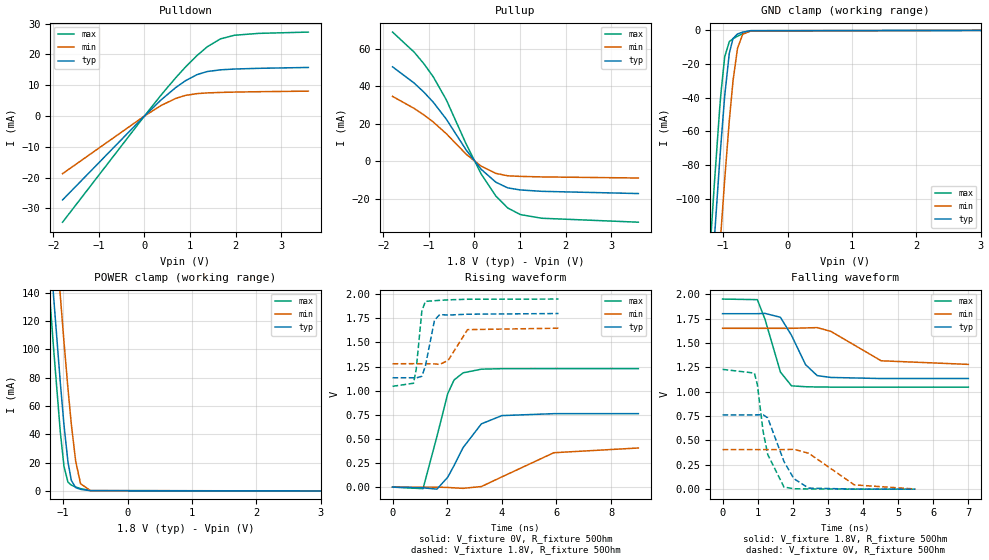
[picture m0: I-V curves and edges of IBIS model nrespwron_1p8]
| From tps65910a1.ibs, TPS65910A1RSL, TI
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|   nrespwron_1p8 Model
[Model]   nrespwron_1p8
Model_type   3-state
Polarity   Non-Inverting
Vmeas = 0.9
Vref = 0
Cref = 35pF
Rref = 150
|   typ   min   max
|   (nom PVT)   (fast PVT)   (slow PVT)
C_comp   6.512e-13   6.210e-13   7.537e-13
| Where nom  PVT is Nominal Process, 1.8V, 27C
|   Fast PVT is Strong Process,  1.95V, -40C
|   Slow PVT is Weak Process,   1.65V, 125C
[Voltage Range]   1.8   1.65   1.95
|Junction Temperature
[Temperature Range]   27   125   -40
[Pullup Reference]   1.8   1.65   1.95
[Pulldown Reference]   0   0   0
[Power Clamp Reference]   1.8   1.65   1.95
[GND Clamp Reference]   0   0   0
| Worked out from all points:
|   slope of the pulldown table from 0 to 0.27 V, typ, clamps not added: 68.9 ohm
|   slope of the pullup table from 0 to 0.27 V, typ, clamps not added: 37.4 ohm
|   GND clamp passes 1 mA (typ) near -0.69 V on its own axis
|   POWER clamp passes 1 mA (typ) near -0.71 V on its own axis
|   falling waveform, V_fixture 1.8V, R_fixture 50Ohm: 20-80 % time 557ps typ, 985ps min, 436ps max; typ from 1.8 V to 1.14 V
|   rising waveform, V_fixture 0V, R_fixture 50Ohm: 20-80 % time 952ps typ, 1.63ns min, 632ps max; typ from 0 V to 0.762 V
|   rising waveform, V_fixture 1.8V, R_fixture 50Ohm: 20-80 % time 265ps typ, 416ps min, 180ps max; typ from 1.13 V to 1.8 V
|   falling waveform, V_fixture 0V, R_fixture 50Ohm: 20-80 % time 472ps typ, 845ps min, 356ps max; typ from 0.762 V to 0 V
[Pulldown]
|   Voltage   I(typ)   I(min)   I(max)
-1.8V     -27.27mA   -18.74mA   -34.5mA
0V        0A         0A         0A
368.4mV   5.271mA    3.439mA    6.872mA
684mV     9.199mA    5.683mA    12.38mA
900mV     11.45mA    6.684mA    15.89mA
1.154V    13.43mA    7.265mA    19.64mA
1.38V     14.44mA    7.493mA    22.48mA
1.667V    14.99mA    7.652mA    25.03mA
1.979V    15.25mA    7.761mA    26.23mA
2.508V    15.48mA    7.885mA    26.83mA
3.6V      15.76mA    8.071mA    27.25mA
[GND Clamp]
|   Voltage   I(typ)   I(min)   I(max)
-1.8V     -537.9mA   -584.9mA   -510.2mA
-1.192V   -156.1mA   -209.6mA   -123.3mA
-1.139V   -125.2mA   -178.8mA   -92.45mA
-1.053V   -76.85mA   -129.7mA   -45.89mA
-1.031V   -65.74mA   -118.1mA   -35.95mA
-975.6mV  -38.78mA   -88.35mA   -15.65mA
-904.1mV  -13.48mA   -53.46mA   -6.697mA
-846.3mV  -4.832mA   -29.82mA   -4.985mA
-777mV    -2.173mA   -10.69mA   -3.501mA
-697.8mV  -1.057mA   -2.45mA    -2.037mA
-571.5mV  -184.3uA   -220.8uA   -441uA
3.6V      0A         0A         0A
[Pullup]
|   Voltage   I(typ)   I(min)   I(max)
-1.8V     50.27mA    34.56mA    68.73mA
-1.322V   41.56mA    28.11mA    57.98mA
-1.108V   36.71mA    24.62mA    51.79mA
-905.7mV  31.46mA    20.92mA    44.94mA
-620.2mV  22.48mA    14.75mA    32.79mA
-180mV    5.972mA    3.772mA    9.076mA
144mV     -4.134mA   -2.496mA   -6.57mA
467.8mV   -11.03mA   -6.349mA   -18.38mA
729.1mV   -14.07mA   -7.65mA    -24.74mA
1.006V    -15.17mA   -7.961mA   -28.24mA
1.474V    -15.9mA    -8.241mA   -30.21mA
3.6V      -17.09mA   -8.824mA   -32.31mA
[POWER Clamp]
|   Voltage   I(typ)   I(min)   I(max)
-1.8V     561.5mA    618.2mA    532.7mA
-1.225V   184.3mA    246.8mA    147.9mA
-1.195V   165.9mA    228.5mA    129.3mA
-1.148V   137.2mA    199.8mA    100.4mA
-1.044V   76.58mA    137.9mA    41.65mA
-986.9mV  46.53mA    105.3mA    17.37mA
-925.5mV  20.52mA    72.5mA     6.199mA
-873mV    7.419mA    47.15mA    4.105mA
-804.6mV  2.31mA     20.71mA    2.774mA
-729.1mV  1.137mA    5.096mA    1.626mA
-575.7mV  171.8uA    225.6uA    209.3uA
3.6V      0A         0A         0A
[Ramp]
R_load = 50
|   typ   min   max
dV/dt_r   0.457066/9.47465e-10   0.24339/1.61303e-09   0.73743/6.3145e-10
dV/dt_f   0.399119/5.55723e-10   0.222299/9.84539e-10   0.542002/4.35702e-10
[Falling Waveform]
V_fixture = 1.8V
V_fixture_min = 1.65V
V_fixture_max = 1.95V
R_fixture = 50Ohm
|   Time   V(typ)   V(min)   V(max)
0s        1.8V       1.65V      1.95V
990ps     1.8V       1.65V      1.944V
1.208ns   1.803V     1.65V      1.743V
1.648ns   1.763V     1.65V      1.201V
1.964ns   1.577V     1.65V      1.06V
2.362ns   1.278V     1.654V     1.051V
2.694ns   1.165V     1.657V     1.048V
3.082ns   1.146V     1.619V     1.047V
4.516ns   1.135V     1.317V     1.047V
6.998ns   1.135V     1.28V      1.047V
[Rising Waveform]
V_fixture = 0V
V_fixture_min = 0V
V_fixture_max = 0V
R_fixture = 50Ohm
|   Time   V(typ)   V(min)   V(max)
0s        257.2pV    515.2pV    248.7pV
1.116ns   -7.118mV   -918.9uV   -16mV
1.624ns   -21.39mV   -628.2uV   524.6mV
2.02ns    102.6mV    -3.625mV   969.8mV
2.252ns   223.7mV    -7.901mV   1.111V
2.582ns   409.7mV    -12.73mV   1.185V
3.252ns   656.1mV    5.759mV    1.223V
4.002ns   741.5mV    105.9mV    1.228V
5.904ns   761.5mV    356.6mV    1.229V
8.998ns   761.8mV    405.6mV    1.229V
[Rising Waveform]
V_fixture = 1.8V
V_fixture_min = 1.65V
V_fixture_max = 1.95V
R_fixture = 50Ohm
|   Time   V(typ)   V(min)   V(max)
0s        1.134V     1.279V     1.045V
768ps     1.134V     1.28V      1.077V
866ps     1.132V     1.28V      1.222V
1.072ns   1.149V     1.279V     1.826V
1.202ns   1.255V     1.28V      1.926V
1.534ns   1.73V      1.278V     1.933V
1.726ns   1.789V     1.272V     1.937V
2.038ns   1.784V     1.315V     1.942V
2.744ns   1.793V     1.633V     1.948V
6.076ns   1.8V       1.648V     1.95V
[Falling Waveform]
V_fixture = 0V
V_fixture_min = 0V
V_fixture_max = 0V
R_fixture = 50Ohm
|   Time   V(typ)   V(min)   V(max)
0s        761.8mV    405.9mV    1.229V
906ps     761.7mV    405.9mV    1.191V
990ps     762.6mV    405.9mV    1.075V
1.154ns   763.1mV    405.9mV    593.2mV
1.286ns   731.4mV    405.9mV    355.1mV
1.748ns   285mV      406mV      22.16mV
2.03ns    108.2mV    409.1mV    4.593mV
2.452ns   10.95mV    368.9mV    2.714mV
3.752ns   1.14mV     44.15mV    701.7uV
5.492ns   346.4uV    1.721mV    279.3uV
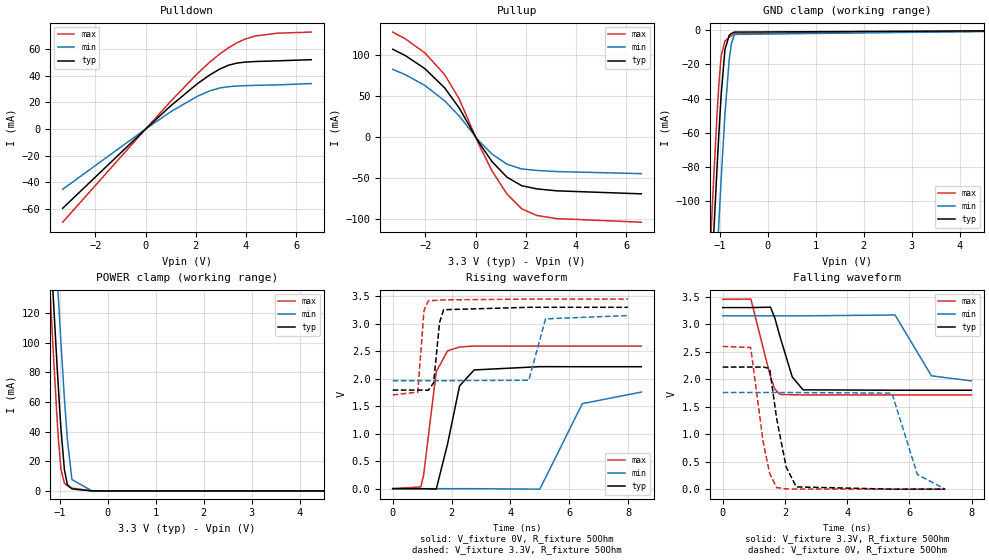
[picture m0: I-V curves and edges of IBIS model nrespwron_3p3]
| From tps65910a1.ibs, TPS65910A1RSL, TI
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|   nrespwron_3p3 Model
[Model]   nrespwron_3p3
Model_type   3-state
Polarity   Non-Inverting
Vmeas = 1.65
Vref = 0
Cref = 35pF
Rref = 50
|   typ   min   max
|   (nom PVT)   (fast PVT)   (slow PVT)
C_comp   7.537e-13   7.138e-13   8.663e-13
| Where nom  PVT is Nominal Process, 3.3V, 27C
|   Fast PVT is Strong Process,  3.45V, -40C
|   Slow PVT is Weak Process,   3.15V, 125C
[Voltage Range]   3.3   3.15   3.45
|Junction Temperature
[Temperature Range]   27   125   -40
[Pullup Reference]   3.3   3.15   3.45
[Pulldown Reference]   0   0   0
[Power Clamp Reference]   3.3   3.15   3.45
[GND Clamp Reference]   0   0   0
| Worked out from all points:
|   slope of the pulldown table from 0 to 0.495 V, typ, clamps not added: 56.3 ohm
|   slope of the pullup table from 0 to 0.495 V, typ, clamps not added: 21.1 ohm
|   GND clamp passes 1 mA (typ) near -0.69 V on its own axis
|   POWER clamp passes 1 mA (typ) near -0.71 V on its own axis
|   falling waveform, V_fixture 3.3V, R_fixture 50Ohm: 20-80 % time 467ps typ, 654ps min, 466ps max; typ from 3.3 V to 1.8 V
|   rising waveform, V_fixture 0V, R_fixture 50Ohm: 20-80 % time 485ps typ, 842ps min, 353ps max; typ from 0 V to 2.22 V
|   rising waveform, V_fixture 3.3V, R_fixture 50Ohm: 20-80 % time 153ps typ, 228ps min, 112ps max; typ from 1.79 V to 3.3 V
|   falling waveform, V_fixture 0V, R_fixture 50Ohm: 20-80 % time 372ps typ, 511ps min, 376ps max; typ from 2.22 V to 0 V
[Pulldown]
|   Voltage   I(typ)   I(min)   I(max)
-3.3V     -59.44mA   -45.17mA   -69.9mA
63.75mV   1.149mA    871uA      1.352mA
1.016V    17.7mA     13.19mA    21.15mA
2.072V    34.21mA    24.72mA    41.83mA
2.555V    40.63mA    28.67mA    50.24mA
2.934V    44.88mA    30.77mA    56.12mA
3.287V    47.86mA    31.81mA    60.86mA
3.633V    49.52mA    32.32mA    64.71mA
3.93V     50.22mA    32.58mA    67.32mA
4.34V     50.71mA    32.82mA    69.81mA
5.259V    51.24mA    33.18mA    72.01mA
6.6V      52.09mA    34.18mA    72.82mA
[GND Clamp]
|   Voltage   I(typ)   I(min)   I(max)
-3.3V     -1.516A    -1.551A    -1.498A
-1.256V   -194.6mA   -247.6mA   -162.1mA
-1.144V   -128mA     -181.6mA   -95.21mA
-1.125V   -117.3mA   -170.9mA   -84.68mA
-1.059V   -80.47mA   -133.4mA   -49.23mA
-1.026V   -63.12mA   -115.3mA   -33.7mA
-973.5mV  -37.86mA   -87.27mA   -15.12mA
-894.3mV  -11.28mA   -49.11mA   -6.315mA
-805.2mV  -2.854mA   -17mA      -4.08mA
-757.3mV  -1.827mA   -7.51mA    -3.115mA
-696.3mV  -1.041mA   -2.383mA   -2.012mA
6.6V      0A         0A         0A
[Pullup]
|   Voltage   I(typ)   I(min)   I(max)
-3.3V     107mA      82.5mA     127.9mA
-2.793V   99.21mA    75.94mA    119.6mA
-2.015V   83.23mA    62.74mA    102.4mA
-1.238V   60.12mA    44.34mA    76.27mA
-650.9mV  35.37mA    25.57mA    46.34mA
117.7mV   -6.05mA    -4.258mA   -8.182mA
656.7mV   -30.03mA   -20.8mA    -41.44mA
1.251V    -48.97mA   -33.13mA   -69.51mA
1.831V    -59.27mA   -38.86mA   -87.35mA
2.436V    -63.2mA    -40.71mA   -95.64mA
3.227V    -65.57mA   -42.07mA   -99.42mA
6.6V      -69.24mA   -44.65mA   -103.8mA
[POWER Clamp]
|   Voltage   I(typ)   I(min)   I(max)
-3.3V     1.593A     1.632A     1.584A
-1.284V   221.5mA    283.7mA    185.7mA
-1.164V   147mA      209.6mA    110.2mA
-1.142V   133.3mA    195.8mA    96.47mA
-1.061V   85.87mA    147.6mA    50.23mA
-1.026V   66.78mA    127.5mA    33mA
-978.5mV  42.5mA     100.6mA    14.85mA
-906mV    14.48mA    62.72mA    5.124mA
-844.8mV  4.234mA    35.12mA    3.503mA
-748.5mV  1.342mA    7.647mA    1.895mA
-330mV    196.2nA    790.2nA    63.89nA
6.6V      0A         0A         0A
[Ramp]
R_load = 50
|   typ   min   max
dV/dt_r   1.33164/4.81138e-10   1.05381/8.35485e-10   1.55658/3.52614e-10
dV/dt_f   0.901403/4.66376e-10   0.708984/6.53085e-10   1.04274/4.66591e-10
[Falling Waveform]
V_fixture = 3.3V
V_fixture_min = 3.15V
V_fixture_max = 3.45V
R_fixture = 50Ohm
|   Time   V(typ)   V(min)   V(max)
0s        3.3V       3.15V      3.45V
904ps     3.3V       3.15V      3.455V
1.536ns   3.307V     3.15V      2.04V
1.674ns   3.113V     3.15V      1.82V
1.842ns   2.77V      3.15V      1.722V
2.234ns   2.041V     3.15V      1.716V
2.584ns   1.805V     3.15V      1.713V
5.54ns    1.798V     3.165V     1.713V
6.708ns   1.798V     2.06V      1.713V
7.99ns    1.798V     1.968V     1.712V
[Rising Waveform]
V_fixture = 0V
V_fixture_min = 0V
V_fixture_max = 0V
R_fixture = 50Ohm
|   Time   V(typ)   V(min)   V(max)
0s        434.3pV    704.1pV    418.1pV
954ps     -1.315mV   -781.5uV   31.28mV
1.05ns    -1.271mV   -809.4uV   246.4mV
1.48ns    -8.283mV   -883.3uV   2.13V
1.866ns   817.7mV    -909.7uV   2.508V
2.272ns   1.869V     -917.3uV   2.578V
2.766ns   2.16V      -920.2uV   2.595V
4.998ns   2.22V      -9.542mV   2.594V
6.444ns   2.219V     1.547V     2.594V
8.448ns   2.219V     1.757V     2.594V
[Rising Waveform]
V_fixture = 3.3V
V_fixture_min = 3.15V
V_fixture_max = 3.45V
R_fixture = 50Ohm
|   Time   V(typ)   V(min)   V(max)
0s        1.794V     1.965V     1.705V
852ps     1.794V     1.965V     1.756V
1.062ns   1.794V     1.965V     3.237V
1.206ns   1.789V     1.965V     3.417V
1.39ns    1.925V     1.965V     3.424V
1.592ns   3.025V     1.965V     3.43V
1.73ns    3.256V     1.965V     3.435V
4.624ns   3.3V       1.972V     3.45V
5.194ns   3.3V       3.09V      3.45V
7.99ns    3.3V       3.15V      3.45V
[Falling Waveform]
V_fixture = 0V
V_fixture_min = 0V
V_fixture_max = 0V
R_fixture = 50Ohm
|   Time   V(typ)   V(min)   V(max)
0s        2.219V     1.756V     2.594V
900ps     2.219V     1.756V     2.574V
1.302ns   2.219V     1.756V     851.8mV
1.508ns   2.195V     1.756V     288.3mV
1.734ns   1.282V     1.756V     29.04mV
2.038ns   405.8mV    1.756V     6.277mV
2.364ns   40.77mV    1.756V     1.735mV
5.438ns   372uV      1.745V     297.5uV
6.256ns   256.9uV    267mV      192.4uV
7.15ns    3.036uV    7.678uV    1.089uV
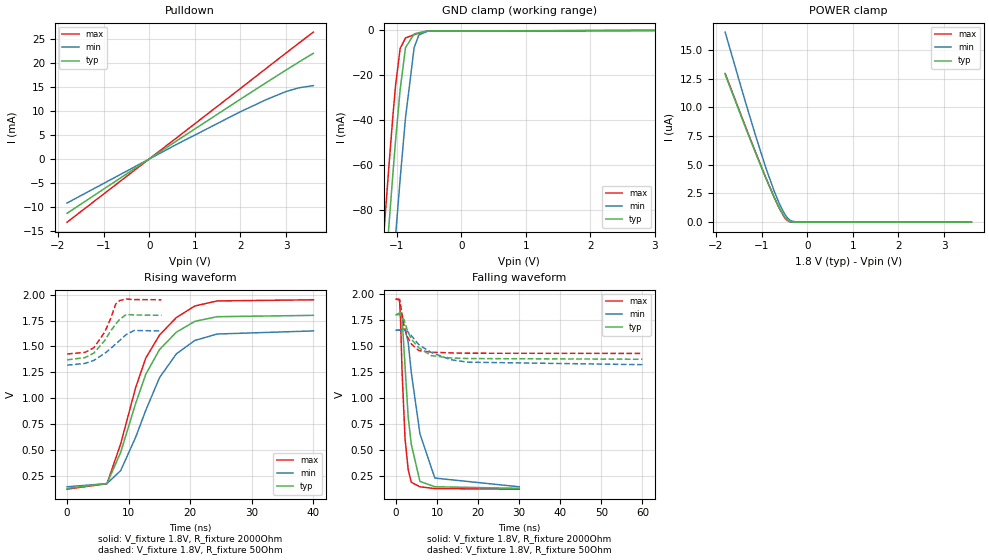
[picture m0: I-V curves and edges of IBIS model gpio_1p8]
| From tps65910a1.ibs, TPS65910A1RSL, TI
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|   gpio_1p8 Model
[Model]   gpio_1p8
Model_type   I/O_open_drain
Polarity   Non-Inverting
Vinl = 0.45
Vinh = 1.3
Vmeas = 0.9
Vref = 1.8
Cref = 2pF
Rref = 2000
|   typ   min   max
|   (nom PVT)   (fast PVT)   (slow PVT)
C_comp   1.855e-13   1.849e-13   1.875e-13
| Where nom  PVT is Nominal Process, 1.8V, 27C
|   Fast PVT is Strong Process,  1.95V, -40C
|   Slow PVT is Weak Process,   1.65V, 125C
[Voltage Range]   1.8   1.65   1.95
|Junction Temperature
[Temperature Range]   27   125   -40
[Pullup Reference]   1.8   1.65   1.95
[Pulldown Reference]   0   0   0
[Power Clamp Reference]   1.8   1.65   1.95
[GND Clamp Reference]   0   0   0
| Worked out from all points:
|   slope of the pulldown table from 0 to 0.27 V, typ, clamps not added: 159 ohm
|   GND clamp passes 1 mA (typ) near -0.65 V on its own axis
|   falling waveform, V_fixture 1.8V, R_fixture 2000Ohm: 20-80 % time 2.04ns typ, 3.65ns min, 1.21ns max; typ from 1.8 V to 0.133 V
|   rising waveform, V_fixture 1.8V, R_fixture 2000Ohm: 20-80 % time 6.33ns typ, 6.78ns min, 6.32ns max; typ from 0.133 V to 1.8 V
|   falling waveform, V_fixture 1.8V, R_fixture 50Ohm: 20-80 % time 4.04ns typ, 7.71ns min, 2.18ns max; typ from 1.8 V to 1.37 V
|   rising waveform, V_fixture 1.8V, R_fixture 50Ohm: 20-80 % time 3.15ns typ, 4.09ns min, 2.55ns max; typ from 1.37 V to 1.8 V
[Pulldown]
|   Voltage   I(typ)   I(min)   I(max)
-1.8V     -11.33mA   -9.187mA   -13.19mA
587.6mV   3.686mA    2.973mA    4.302mA
1.982V    12.35mA    9.763mA    14.56mA
2.563V    15.91mA    12.36mA    18.87mA
2.985V    18.45mA    14.01mA    21.98mA
3.278V    20.19mA    14.83mA    24.13mA
3.6V      22.04mA    15.3mA     26.46mA
[GND Clamp]
|   Voltage   I(typ)   I(min)   I(max)
-1.8V     -361.8mA   -403.7mA   -337.2mA
-1.203V   -118.8mA   -162.5mA   -92.21mA
-1.166V   -104.5mA   -148.2mA   -77.89mA
-1.121V   -87.3mA    -130.8mA   -60.83mA
-1.057V   -63.28mA   -106.3mA   -37.54mA
-1.015V   -48.43mA   -90.75mA   -23.96mA
-946.8mV  -26.57mA   -66.49mA   -8.136mA
-864mV    -7.747mA   -39.17mA   -3.402mA
-729.5mV  -1.628mA   -7.669mA   -1.964mA
-656.5mV  -1.052mA   -2.096mA   -1.315mA
-519.6mV  -273.7uA   -364.3uA   -354.4uA
3.6V      0A         0A         0A
[POWER Clamp]
|   Voltage   I(typ)   I(min)   I(max)
-1.8V     12.87uA    16.54uA    12.94uA
-1.377V   8.475uA    10.75uA    8.557uA
-1.12V    5.898uA    7.37uA     5.957uA
-900mV    3.768uA    4.644uA    3.793uA
-721.8mV  2.149uA    2.672uA    2.133uA
-613.7mV  1.258uA    1.637uA    1.213uA
-501.4mV  495.5nA    758.6nA    427.2nA
-442mV    219.1nA    414.3nA    159.9nA
-390.9mV  82.21nA    208.7nA    46.89nA
-338.1mV  23.13nA    87.27nA    0A
-180mV    0A         0A         0A
3.6V      0A         0A         0A
[Ramp]
R_load = 2000
|   typ   min   max
dV/dt_r   1.00032/6.33276e-09   0.901279/6.73223e-09   1.09514/6.32021e-09
dV/dt_f   1.00046/2.02265e-09   0.901472/3.64339e-09   1.09525/1.2112e-09
[Falling Waveform]
V_fixture = 1.8V
V_fixture_min = 1.65V
V_fixture_max = 1.95V
R_fixture = 2000Ohm
|   Time   V(typ)   V(min)   V(max)
0s        1.8V       1.65V      1.95V
824ps     1.815V     1.653V     1.948V
1.094ns   1.819V     1.657V     1.742V
1.452ns   1.766V     1.663V     1.25V
2.18ns    1.303V     1.659V     607.3mV
2.938ns   819.3mV    1.536V     313.2mV
3.692ns   556.1mV    1.246V     190.7mV
5.802ns   199.2mV    656.6mV    147.3mV
9.438ns   147.7mV    231.1mV    130.2mV
30ns      132.6mV    147.5mV    124.6mV
[Rising Waveform]
V_fixture = 1.8V
V_fixture_min = 1.65V
V_fixture_max = 1.95V
R_fixture = 2000Ohm
|   Time   V(typ)   V(min)   V(max)
0s        132.6mV    147.5mV    124.6mV
6.48ns    179.4mV    178.3mV    177.5mV
8.702ns   479.2mV    303.9mV    561.1mV
11.16ns   955.9mV    628.4mV    1.109V
12.78ns   1.232V     884.9mV    1.388V
15.02ns   1.471V     1.201V     1.611V
17.75ns   1.638V     1.429V     1.779V
20.74ns   1.742V     1.558V     1.89V
24.36ns   1.787V     1.62V      1.939V
40ns      1.8V       1.65V      1.95V
[Falling Waveform]
V_fixture = 1.8V
V_fixture_min = 1.65V
V_fixture_max = 1.95V
R_fixture = 50Ohm
|   Time   V(typ)   V(min)   V(max)
0s        1.8V       1.65V      1.95V
890ps     1.802V     1.651V     1.939V
1.926ns   1.751V     1.651V     1.691V
2.734ns   1.65V      1.64V      1.589V
3.718ns   1.564V     1.599V     1.518V
5.498ns   1.484V     1.513V     1.456V
8.53ns    1.407V     1.438V     1.44V
13.17ns   1.385V     1.369V     1.433V
17.38ns   1.379V     1.344V     1.43V
60ns      1.372V     1.32V      1.428V
[Rising Waveform]
V_fixture = 1.8V
V_fixture_min = 1.65V
V_fixture_max = 1.95V
R_fixture = 50Ohm
|   Time   V(typ)   V(min)   V(max)
0s        1.371V     1.32V      1.427V
2.942ns   1.393V     1.337V     1.444V
4.35ns    1.437V     1.366V     1.488V
6.116ns   1.557V     1.434V     1.639V
7.004ns   1.643V     1.476V     1.759V
7.892ns   1.716V     1.524V     1.908V
8.558ns   1.762V     1.559V     1.944V
9.604ns   1.808V     1.615V     1.957V
10.9ns    1.804V     1.654V     1.952V
15.33ns   1.8V       1.65V      1.95V
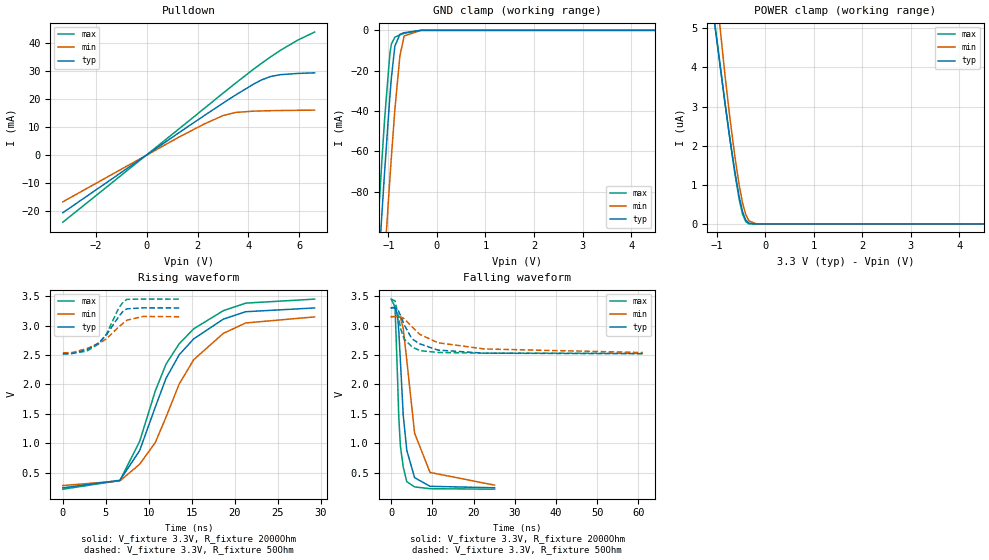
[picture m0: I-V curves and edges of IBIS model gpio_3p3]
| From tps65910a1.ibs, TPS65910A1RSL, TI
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|   gpio_3p3 Model
[Model]   gpio_3p3
Model_type   I/O_open_drain
Polarity   Non-Inverting
Vinl = 0.45
Vinh = 1.3
Vmeas = 1.65
Vref = 3.3
Cref = 2pF
Rref = 2000
|   typ   min   max
|   (nom PVT)   (fast PVT)   (slow PVT)
C_comp   1.720e-13   1.720e-13   1.735e-13
| Where nom  PVT is Nominal Process, 3.3V, 27C
|   Fast PVT is Strong Process,  3.45V, -40C
|   Slow PVT is Weak Process,   3.15V, 125C
[Voltage Range]   3.3   3.15   3.45
|Junction Temperature
[Temperature Range]   27   125   -40
[Pullup Reference]   3.3   3.15   3.45
[Pulldown Reference]   0   0   0
[Power Clamp Reference]   3.3   3.15   3.45
[GND Clamp Reference]   0   0   0
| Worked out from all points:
|   slope of the pulldown table from 0 to 0.495 V, typ, clamps not added: 159 ohm
|   GND clamp passes 1 mA (typ) near -0.65 V on its own axis
|   falling waveform, V_fixture 3.3V, R_fixture 2000Ohm: 20-80 % time 1.83ns typ, 3.47ns min, 1.1ns max; typ from 3.3 V to 0.245 V
|   rising waveform, V_fixture 3.3V, R_fixture 2000Ohm: 20-80 % time 5.76ns typ, 6.14ns min, 5.69ns max; typ from 0.243 V to 3.3 V
|   falling waveform, V_fixture 3.3V, R_fixture 50Ohm: 20-80 % time 4.91ns typ, 10.6ns min, 2.37ns max; typ from 3.3 V to 2.52 V
|   rising waveform, V_fixture 3.3V, R_fixture 50Ohm: 20-80 % time 2.59ns typ, 3.21ns min, 2.08ns max; typ from 2.52 V to 3.3 V
[Pulldown]
|   Voltage   I(typ)   I(min)   I(max)
-3.3V     -20.79mA   -16.87mA   -24.19mA
1.251V    7.821mA    6.261mA    9.166mA
2.263V    14.08mA    11.05mA    16.64mA
3.003V    18.56mA    14.07mA    22.12mA
3.485V    21.39mA    15.18mA    25.64mA
4.181V    25.24mA    15.64mA    30.57mA
4.511V    26.84mA    15.73mA    32.8mA
4.881V    28.11mA    15.81mA    35.19mA
5.255V    28.73mA    15.87mA    37.46mA
5.943V    29.18mA    15.95mA    41.15mA
6.6V      29.39mA    16.02mA    44.01mA
[GND Clamp]
|   Voltage   I(typ)   I(min)   I(max)
-3.3V     -995.3mA   -1.032A    -974.9mA
-1.261V   -141.4mA   -185mA     -114.9mA
-1.233V   -130.6mA   -174.3mA   -104.1mA
-1.13V    -90.54mA   -134.1mA   -64.03mA
-1.073V   -69.24mA   -112.4mA   -43.22mA
-967.8mV  -32.95mA   -73.87mA   -11.83mA
-936.7mV  -23.68mA   -63.02mA   -6.838mA
-864.6mV  -7.833mA   -39.35mA   -3.411mA
-761.1mV  -1.984mA   -12.75mA   -2.265mA
-672.9mV  -1.169mA   -2.773mA   -1.455mA
-330mV    -3.122uA   -16.64uA   -1.841uA
6.6V      0A         0A         0A
[POWER Clamp]
|   Voltage   I(typ)   I(min)   I(max)
-3.3V     29.81uA    37.71uA    28.94uA
-1.233V   7.025uA    8.845uA    7.097uA
-1.073V   5.433uA    6.768uA    5.486uA
-827.3mV  3.092uA    3.807uA    3.102uA
-723.3mV  2.162uA    2.688uA    2.147uA
-625.7mV  1.352uA    1.745uA    1.31uA
-534.6mV  695.2nA    992.7nA    630.6nA
-465.3mV  313.2nA    537.8nA    247.6nA
-398.8mV  97.62nA    235.9nA    58.25nA
-330mV    18.87nA    76.62nA    0A
-178.4mV  0A         0A         0A
6.6V      0A         0A         0A
[Ramp]
R_load = 2000
|   typ   min   max
dV/dt_r   1.83398/5.75567e-09   1.72056/6.11299e-09   1.93763/5.66895e-09
dV/dt_f   1.83409/1.82305e-09   1.72071/3.47328e-09   1.93772/1.09895e-09
[Falling Waveform]
V_fixture = 3.3V
V_fixture_min = 3.15V
V_fixture_max = 3.45V
R_fixture = 2000Ohm
|   Time   V(typ)   V(min)   V(max)
0s        3.3V       3.15V      3.45V
944ps     3.315V     3.154V     3.318V
1.558ns   3.164V     3.161V     2.104V
1.844ns   2.923V     3.161V     1.46V
2.248ns   2.396V     3.136V     949.4mV
2.94ns    1.47V      2.946V     594.7mV
3.794ns   881mV      2.412V     348.2mV
5.692ns   416.9mV    1.172V     259.7mV
9.444ns   269.3mV    504.8mV    228.8mV
25.11ns   244.6mV    289.6mV    220.9mV
[Rising Waveform]
V_fixture = 3.3V
V_fixture_min = 3.15V
V_fixture_max = 3.45V
R_fixture = 2000Ohm
|   Time   V(typ)   V(min)   V(max)
0s        243.2mV    282.1mV    220.5mV
6.626ns   371.4mV    360.5mV    366.5mV
8.926ns   875.3mV    643.9mV    1.03V
10.74ns   1.613V     1.011V     1.887V
12ns      2.106V     1.447V     2.346V
13.53ns   2.505V     2.008V     2.692V
15.21ns   2.774V     2.42V      2.945V
18.65ns   3.109V     2.867V     3.253V
21.26ns   3.236V     3.045V     3.382V
29.27ns   3.3V       3.148V     3.45V
[Falling Waveform]
V_fixture = 3.3V
V_fixture_min = 3.15V
V_fixture_max = 3.45V
R_fixture = 50Ohm
|   Time   V(typ)   V(min)   V(max)
0s        3.3V       3.15V      3.45V
950ps     3.302V     3.151V     3.418V
1.596ns   3.273V     3.151V     3.203V
2.338ns   3.162V     3.145V     2.941V
3.16ns    3.014V     3.116V     2.77V
5.036ns   2.775V     2.98V      2.64V
6.95ns    2.689V     2.851V     2.574V
11.36ns   2.583V     2.708V     2.543V
22.65ns   2.531V     2.602V     2.531V
61.11ns   2.521V     2.542V     2.528V
[Rising Waveform]
V_fixture = 3.3V
V_fixture_min = 3.15V
V_fixture_max = 3.45V
R_fixture = 50Ohm
|   Time   V(typ)   V(min)   V(max)
0s        2.518V     2.537V     2.522V
1.042ns   2.525V     2.541V     2.527V
2.78ns    2.587V     2.609V     2.566V
4.188ns   2.709V     2.695V     2.69V
5.066ns   2.842V     2.775V     2.856V
6.538ns   3.163V     2.984V     3.311V
7.06ns    3.253V     3.047V     3.407V
7.452ns   3.285V     3.092V     3.446V
9.34ns    3.302V     3.156V     3.451V
13.53ns   3.3V       3.15V      3.45V
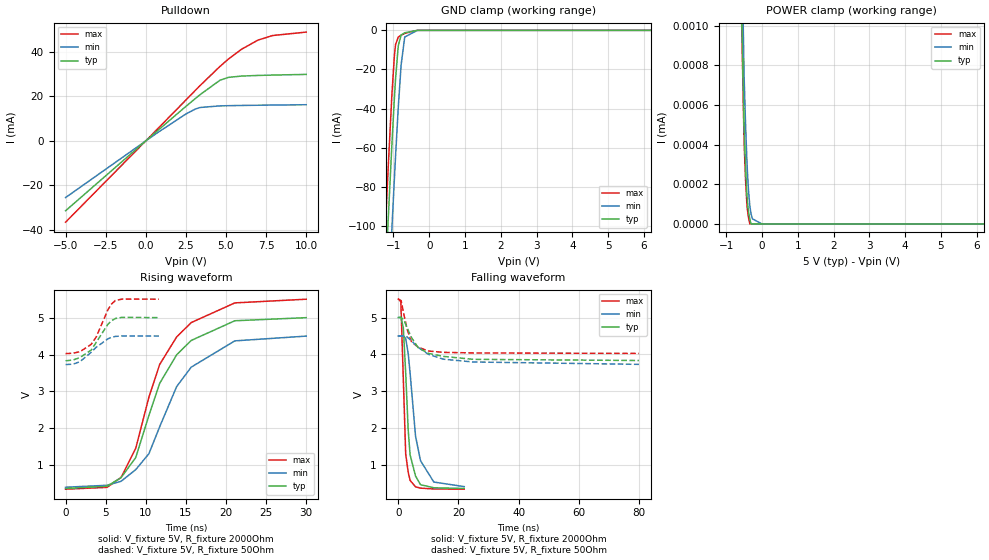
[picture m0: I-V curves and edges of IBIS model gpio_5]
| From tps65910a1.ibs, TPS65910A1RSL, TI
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|   gpio_5 Model
[Model]   gpio_5
Model_type   I/O_open_drain
Polarity   Non-Inverting
Vinl = 0.45
Vinh = 1.3
Vmeas = 2.5
Vref = 5
Cref = 2pF
Rref = 2000
|   typ   min   max
|   (nom PVT)   (fast PVT)   (slow PVT)
C_comp   1.623e-13   1.612e-13   1.652e-13
| Where nom  PVT is Nominal Process, 5V, 27C
|   Fast PVT is Strong Process,  5.5V, -40C
|   Slow PVT is Weak Process,   4.5V, 125C
[Voltage Range]   5   4.5   5.5
|Junction Temperature
[Temperature Range]   27   125   -40
[Pullup Reference]   5   4.5   5.5
[Pulldown Reference]   0   0   0
[Power Clamp Reference]   5   4.5   5.5
[GND Clamp Reference]   0   0   0
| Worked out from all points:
|   slope of the pulldown table from 0 to 0.75 V, typ, clamps not added: 160 ohm
|   GND clamp passes 1 mA (typ) near -0.64 V on its own axis
|   falling waveform, V_fixture 5V, R_fixture 2000Ohm: 20-80 % time 1.76ns typ, 3.18ns min, 1.09ns max; typ from 5 V to 0.372 V
|   rising waveform, V_fixture 5V, R_fixture 2000Ohm: 20-80 % time 5.26ns typ, 5.63ns min, 5.19ns max; typ from 0.369 V to 5 V
|   falling waveform, V_fixture 5V, R_fixture 50Ohm: 20-80 % time 5.93ns typ, 9.58ns min, 2.96ns max; typ from 5 V to 3.84 V
|   rising waveform, V_fixture 5V, R_fixture 50Ohm: 20-80 % time 2.1ns typ, 2.32ns min, 1.89ns max; typ from 3.83 V to 5 V
[Pulldown]
|   Voltage   I(typ)   I(min)   I(max)
-5V       -31.51mA   -25.56mA   -36.65mA
700mV     4.389mA    3.537mA    5.126mA
2.497V    15.5mA     12.08mA    18.37mA
3.082V    19.03mA    14.32mA    22.7mA
3.393V    20.86mA    15.04mA    24.97mA
4.62V     27.29mA    15.76mA    33.52mA
5.142V    28.59mA    15.85mA    36.79mA
5.955V    29.19mA    15.95mA    41.21mA
6.979V    29.47mA    16.05mA    45.35mA
7.897V    29.64mA    16.13mA    47.45mA
10V       29.94mA    16.28mA    49.01mA
[GND Clamp]
|   Voltage   I(typ)   I(min)   I(max)
-5V       -1.721A    -1.754A    -1.705A
-1.31V    -160.8mA   -204.4mA   -134.4mA
-1.193V   -114.8mA   -158.5mA   -88.19mA
-1.145V   -96.28mA   -139.9mA   -69.72mA
-1.045V   -59.11mA   -102mA     -33.63mA
-974mV    -34.92mA   -76.08mA   -13.16mA
-941mV    -24.89mA   -64.48mA   -7.349mA
-865mV    -7.89mA    -39.48mA   -3.418mA
-785mV    -2.398mA   -17.71mA   -2.498mA
-684.5mV  -1.255mA   -3.412mA   -1.557mA
-330.5mV  -3.172uA   -16.83uA   -1.876uA
10V       0A         0A         0A
[POWER Clamp]
|   Voltage   I(typ)   I(min)   I(max)
-5V       1.229mA    1.277mA    1.674mA
-1.081V   5.507uA    6.865uA    5.561uA
-500mV    487.8nA    751.5nA    419.5nA
-460mV    290.3nA    509.8nA    225.9nA
-424mV    160.4nA    334nA      108.5nA
-405.5mV  112.2nA    260.7nA    69.52nA
-374mV    56.63nA    162.9nA    29.35nA
-338mV    23.53nA    89.57nA    0A
-305mV    0A         50.38nA    0A
-265mV    0A         25.8nA     0A
-500uV    0A         0A         0A
10V       0A         0A         0A
[Ramp]
R_load = 2000
|   typ   min   max
dV/dt_r   2.7786/5.25057e-09   2.45755/5.60852e-09   3.08894/5.18135e-09
dV/dt_f   2.77876/1.76589e-09   2.4577/3.22107e-09   3.08905/1.08948e-09
[Falling Waveform]
V_fixture = 5V
V_fixture_min = 4.5V
V_fixture_max = 5.5V
R_fixture = 2000Ohm
|   Time   V(typ)   V(min)   V(max)
0s        5V         4.5V       5.5V
836ps     5.011V     4.502V     5.43V
1.658ns   4.732V     4.511V     3.35V
2.456ns   3.496V     4.432V     1.303V
3.294ns   1.946V     4.02V      808mV
3.912ns   1.284V     3.504V     591.6mV
5.728ns   708.1mV    1.787V     414.9mV
7.376ns   473.4mV    1.124V     380.7mV
11.81ns   390mV      545.1mV    357.8mV
21.91ns   372.3mV    421.6mV    352.5mV
[Rising Waveform]
V_fixture = 5V
V_fixture_min = 4.5V
V_fixture_max = 5.5V
R_fixture = 2000Ohm
|   Time   V(typ)   V(min)   V(max)
0s        368.7mV    403.7mV    351.5mV
5.172ns   430.4mV    457.1mV    399.9mV
6.918ns   663.6mV    564.5mV    669.8mV
8.752ns   1.21V      881.9mV    1.461V
10.38ns   2.343V     1.309V     2.837V
11.73ns   3.218V     2.041V     3.731V
13.85ns   3.994V     3.133V     4.478V
15.66ns   4.382V     3.658V     4.866V
21.1ns    4.916V     4.371V     5.4V
30ns      5V         4.5V       5.5V
[Falling Waveform]
V_fixture = 5V
V_fixture_min = 4.5V
V_fixture_max = 5.5V
R_fixture = 50Ohm
|   Time   V(typ)   V(min)   V(max)
0s        5V         4.5V       5.5V
950ps     5.001V     4.501V     5.457V
1.822ns   4.938V     4.5V       5.102V
2.88ns    4.734V     4.476V     4.691V
4.352ns   4.46V      4.371V     4.348V
6.592ns   4.185V     4.192V     4.198V
10ns      4.03V      4.004V     4.093V
14.97ns   3.948V     3.872V     4.057V
24.89ns   3.868V     3.796V     4.041V
80ns      3.836V     3.732V     4.028V
[Rising Waveform]
V_fixture = 5V
V_fixture_min = 4.5V
V_fixture_max = 5.5V
R_fixture = 50Ohm
|   Time   V(typ)   V(min)   V(max)
0s        3.832V     3.729V     4.025V
914ps     3.85V      3.738V     4.037V
1.788ns   3.918V     3.806V     4.076V
3.198ns   4.122V     4.062V     4.277V
3.814ns   4.328V     4.197V     4.474V
5.282ns   4.823V     4.427V     5.215V
5.738ns   4.917V     4.467V     5.371V
6.206ns   4.977V     4.492V     5.465V
7.064ns   5.008V     4.504V     5.504V
11.64ns   5V         4.5V       5.5V
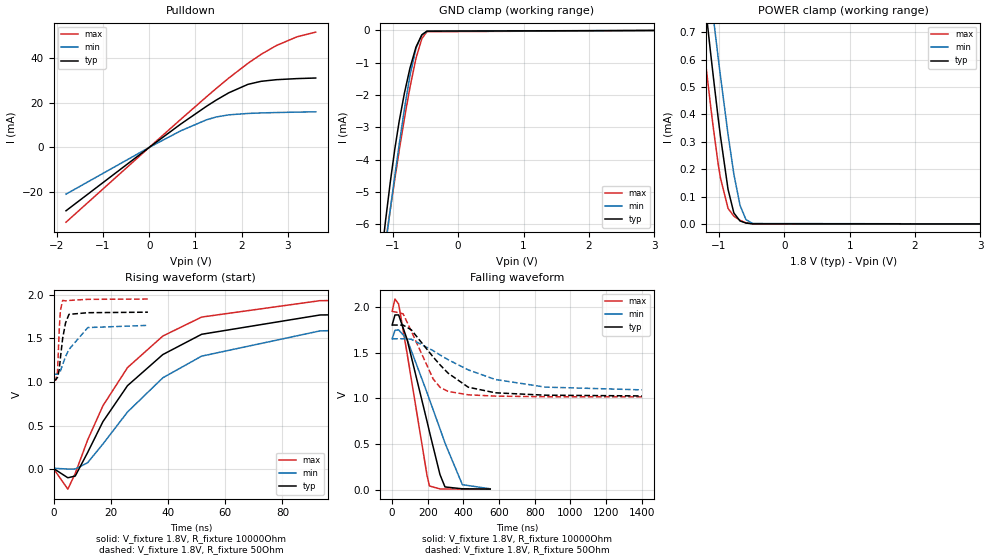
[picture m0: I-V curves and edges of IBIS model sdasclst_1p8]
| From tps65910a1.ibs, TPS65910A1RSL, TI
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|   sdasclst_1p8 Model
[Model]   sdasclst_1p8
Model_type   I/O_open_drain
Polarity   Non-Inverting
Vinl = 0.54
Vinh = 1.26
Vmeas = 0.9
Vref = 1.8
Cref = 400pF
Rref = 10000
|   typ   min   max
|   (nom PVT)   (fast PVT)   (slow PVT)
C_comp   9.733e-14   7.243e-14   1.141e-13
[Model spec]
|subparameter
Vinl   0.54   0.495   0.585
Vinh   1.26   1.155   1.365
| Where nom  PVT is Nominal Process, 1.8V, 27C
|   Fast PVT is Strong Process,  1.95V, -40C
|   Slow PVT is Weak Process,   1.65V, 125C
[Voltage Range]   1.8   1.65   1.95
|Junction Temperature
[Temperature Range]   27   125   -40
[Pullup Reference]   1.8   1.65   1.95
[Pulldown Reference]   0   0   0
[Power Clamp Reference]   1.8   1.65   1.95
[GND Clamp Reference]   0   0   0
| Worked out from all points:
|   slope of the pulldown table from 0 to 0.27 V, typ, clamps not added: 64.2 ohm
|   GND clamp passes 1 mA (typ) near -0.71 V on its own axis
|   POWER clamp passes 1 mA (typ) near -1.30 V on its own axis
|   falling waveform, V_fixture 1.8V, R_fixture 10000Ohm: 20-80 % time 134ns typ, 181ns min, 97.6ns max; typ from 1.8 V to 0.011 V
|   rising waveform, V_fixture 1.8V, R_fixture 10000Ohm: 20-80 % time 30.1ns typ, 35.3ns min, 27.2ns max; typ from 0.011 V to 1.8 V
|   falling waveform, V_fixture 1.8V, R_fixture 50Ohm: 20-80 % time 220ns typ, 365ns min, 132ns max; typ from 1.8 V to 1.03 V
|   rising waveform, V_fixture 1.8V, R_fixture 50Ohm: 20-80 % time 1.85ns typ, 5.66ns min, 762ps max; typ from 1.03 V to 1.8 V
[Pulldown]
|   Voltage   I(typ)   I(min)   I(max)
-1.8V     -28.34mA   -20.91mA   -33.45mA
34.95mV   549uA      403uA      649.1uA
684mV     10.48mA    7.449mA    12.6mA
1.238V    18.38mA    12.33mA    22.63mA
1.447V    21.14mA    13.6mA     26.33mA
1.721V    24.43mA    14.56mA    31.03mA
2.135V    28.2mA     15.18mA    37.61mA
2.418V    29.55mA    15.41mA    41.6mA
2.749V    30.28mA    15.59mA    45.55mA
3.198V    30.77mA    15.78mA    49.48mA
3.6V      31.03mA    15.91mA    51.57mA
[GND Clamp]
|   Voltage   I(typ)   I(min)   I(max)
-1.8V     -19.24mA   -17.89mA   -19.68mA
-1.208V   -7.627mA   -8.181mA   -8.006mA
-1.112V   -5.921mA   -6.676mA   -6.595mA
-1.037V   -4.687mA   -5.527mA   -5.539mA
-968.4mV  -3.673mA   -4.501mA   -4.605mA
-901.8mV  -2.818mA   -3.535mA   -3.726mA
-820.8mV  -1.937mA   -2.426mA   -2.718mA
-735.8mV  -1.163mA   -1.391mA   -1.754mA
-643.3mV  -511.1uA   -549.4uA   -855uA
-554.3mV  -137.5uA   -140.3uA   -254.8uA
-477mV    -25.17uA   -30.69uA   -42.82uA
3.6V      0A         0A         0A
[POWER Clamp]
|   Voltage   I(typ)   I(min)   I(max)
-1.8V     2.198mA    2.387mA    1.947mA
-1.269V   932.8uA    1.137mA    723uA
-1.123V   617.8uA    832.7uA    424.9uA
-1.082V   532.4uA    749.8uA    346.2uA
-1.012V   389.7uA    609.9uA    221.5uA
-977.4mV  323.6uA    543.8uA    170.1uA
-859.5mV  126.3uA    326.8uA    56.77uA
-770.4mV  40.09uA    181.8uA    28.37uA
-676.4mV  10.97uA    67.86uA    13.4uA
-585.6mV  3.31uA     15.84uA    3.968uA
-483.3mV  385.1nA    1.578uA    290.9nA
3.6V      0A         0A         0A
[Ramp]
R_load = 10000
|   typ   min   max
dV/dt_r   1.07315/3.00065e-08   0.981476/3.52096e-08   1.16371/2.71762e-08
dV/dt_f   1.07313/1.33372e-07   0.981311/1.80547e-07   1.16373/9.73779e-08
[Falling Waveform]
V_fixture = 1.8V
V_fixture_min = 1.65V
V_fixture_max = 1.95V
R_fixture = 10000Ohm
|   Time   V(typ)   V(min)   V(max)
0s        1.8V       1.65V      1.95V
15.92ns   1.91V      1.742V     2.083V
36.42ns   1.91V      1.747V     2.029V
83.26ns   1.647V     1.646V     1.498V
196ns     747mV      1.061V     156.5mV
209.3ns   636mV      988mV      45.14mV
268.3ns   169.2mV    668.6mV    13.17mV
296.3ns   34.9mV     513.7mV    12.25mV
393.8ns   14.33mV    59.33mV    11.1mV
550ns     11.45mV    14.48mV    10.45mV
[Rising Waveform]
V_fixture = 1.8V
V_fixture_min = 1.65V
V_fixture_max = 1.95V
R_fixture = 10000Ohm
|   Time   V(typ)   V(min)   V(max)
0s        11.38mV    14.17mV    10.44mV
5ns       -94.63mV   5.062mV    -225.1mV
7.58ns    -74.99mV   5.433mV    -45.7mV
11.9ns    192.9mV    77.12mV    336mV
17.26ns   547.1mV    291.4mV    728.8mV
25.86ns   959.3mV    658mV      1.166V
38.2ns    1.315V     1.049V     1.527V
51.76ns   1.547V     1.297V     1.744V
93.18ns   1.768V     1.586V     1.932V
183.2ns   1.8V       1.65V      1.95V
[Falling Waveform]
V_fixture = 1.8V
V_fixture_min = 1.65V
V_fixture_max = 1.95V
R_fixture = 50Ohm
|   Time   V(typ)   V(min)   V(max)
0s        1.8V       1.65V      1.95V
61.8ns    1.799V     1.65V      1.922V
107.2ns   1.748V     1.645V     1.734V
229.8ns   1.452V     1.521V     1.213V
268.4ns   1.366V     1.474V     1.121V
313.8ns   1.275V     1.422V     1.076V
426.8ns   1.122V     1.311V     1.039V
578.6ns   1.061V     1.206V     1.025V
859.4ns   1.035V     1.123V     1.018V
1.4us     1.027V     1.093V     1.017V
[Rising Waveform]
V_fixture = 1.8V
V_fixture_min = 1.65V
V_fixture_max = 1.95V
R_fixture = 50Ohm
|   Time   V(typ)   V(min)   V(max)
0s        1.027V     1.09V      1.017V
800ps     1.027V     1.09V      1.025V
1.4ns     1.055V     1.09V      1.122V
2ns       1.146V     1.1V       1.602V
2.4ns     1.275V     1.126V     1.82V
3.2ns     1.503V     1.201V     1.935V
4.2ns     1.677V     1.292V     1.929V
5.4ns     1.775V     1.374V     1.934V
12ns      1.794V     1.624V     1.947V
33ns      1.8V       1.649V     1.95V
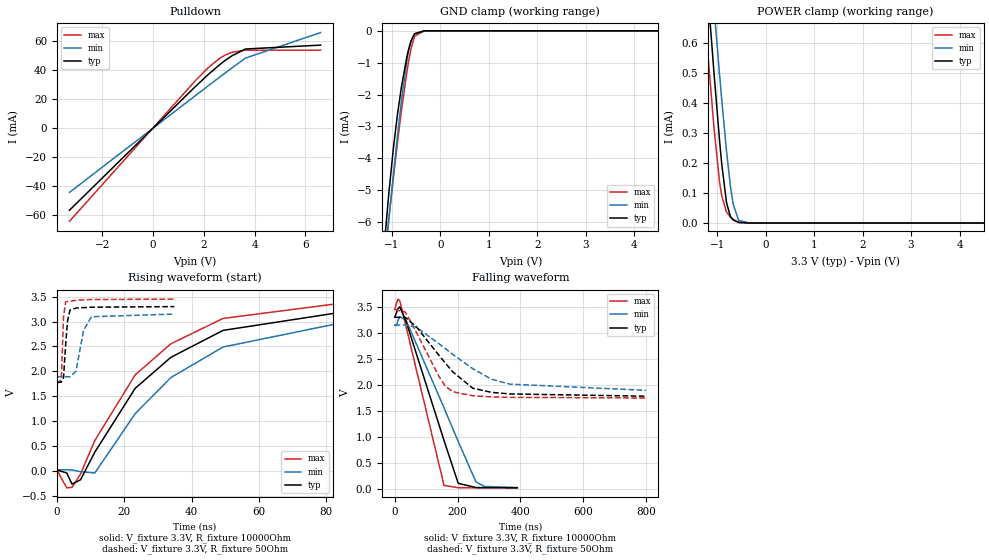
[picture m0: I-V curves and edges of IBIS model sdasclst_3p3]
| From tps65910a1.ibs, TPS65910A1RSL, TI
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|   sdasclst_3p3 Model
[Model]   sdasclst_3p3
Model_type   I/O_open_drain
Polarity   Non-Inverting
Vinl = 0.99
Vinh = 2.31
Vmeas = 1.65
Vref = 3.3
Cref = 400pF
Rref = 10000
|   typ   min   max
|   (nom PVT)   (fast PVT)   (slow PVT)
C_comp   6.141e-14   5.248e-14   6.765e-14
[Model spec]
|subparameter
Vinl   0.99   0.945   1.035
Vinh   2.31   2.205   2.415
| Where nom  PVT is Nominal Process, 3.3V, 27C
|   Fast PVT is Strong Process,  3.45V, -40C
|   Slow PVT is Weak Process,   3.15V, 125C
[Voltage Range]   3.3   3.15   3.45
|Junction Temperature
[Temperature Range]   27   125   -40
[Pullup Reference]   3.3   3.15   3.45
[Pulldown Reference]   0   0   0
[Power Clamp Reference]   3.3   3.15   3.45
[GND Clamp Reference]   0   0   0
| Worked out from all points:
|   slope of the pulldown table from 0 to 0.495 V, typ, clamps not added: 58.3 ohm
|   GND clamp passes 1 mA (typ) near -0.71 V on its own axis
|   POWER clamp passes 1 mA (typ) near -1.30 V on its own axis
|   falling waveform, V_fixture 3.3V, R_fixture 10000Ohm: 20-80 % time 103ns typ, 131ns min, 79.6ns max; typ from 3.3 V to 0.019 V
|   rising waveform, V_fixture 3.3V, R_fixture 10000Ohm: 20-80 % time 29.5ns typ, 32.6ns min, 27.1ns max; typ from 0.019 V to 3.3 V
|   falling waveform, V_fixture 3.3V, R_fixture 50Ohm: 20-80 % time 126ns typ, 176ns min, 87.9ns max; typ from 3.3 V to 1.78 V
|   rising waveform, V_fixture 3.3V, R_fixture 50Ohm: 20-80 % time 853ps typ, 2.24ns min, 456ps max; typ from 1.78 V to 3.3 V
[Pulldown]
|   Voltage   I(typ)   I(min)   I(max)
-3.3V     -56.75mA   -44.46mA   -64.36mA
1.645V    28.15mA    21.96mA    32.17mA
2.158V    36.57mA    28.78mA    41.32mA
2.637V    43.76mA    35.14mA    48.1mA
2.833V    46.39mA    37.72mA    50.11mA
3.114V    49.74mA    41.39mA    52.13mA
3.635V    54.33mA    48.04mA    53.51mA
6.6V      57.01mA    65.66mA    53.51mA
[GND Clamp]
|   Voltage   I(typ)   I(min)   I(max)
-3.3V     -48.39mA   -44.92mA   -50.25mA
-1.164V   -6.846mA   -7.5mA     -7.361mA
-1.063V   -5.1mA     -5.92mA    -5.899mA
-971.2mV  -3.713mA   -4.544mA   -4.643mA
-884.4mV  -2.615mA   -3.29mA    -3.503mA
-802.1mV  -1.754mA   -2.183mA   -2.497mA
-691.8mV  -824.8uA   -943.6uA   -1.301mA
-656.7mV  -590.7uA   -646.3uA   -971.5uA
-605.6mV  -317.6uA   -327uA     -558.5uA
-533.1mV  -90.79uA   -94.86uA   -168.5uA
-330mV    -364nA     -1.09uA    -250.7nA
6.6V      0A         0A         0A
[POWER Clamp]
|   Voltage   I(typ)   I(min)   I(max)
-3.3V     6.427mA    5.735mA    6.456mA
-1.353V   1.121mA    1.32mA     903.5uA
-1.196V   772.1uA    982uA      570uA
-1.064V   495.7uA    714.1uA    313.1uA
-950.4mV  273.4uA    492.5uA    135.5uA
-907.5mV  198.7uA    412.7uA    91.66uA
-808.5mV  68.66uA    240.8uA    36.76uA
-726.3mV  20.89uA    121.5uA    20.71uA
-671.1mV  10.3uA     63.31uA    12.71uA
-556.4mV  1.987uA    8.722uA    2.191uA
-330mV    0A         27.99nA    0A
6.6V      0A         0A         0A
[Ramp]
R_load = 10000
|   typ   min   max
dV/dt_r   1.96851/2.94508e-08   1.87603/3.25536e-08   2.0594/2.70608e-08
dV/dt_f   1.96853/1.03367e-07   1.87598/1.31013e-07   2.05943/7.96504e-08
[Falling Waveform]
V_fixture = 3.3V
V_fixture_min = 3.15V
V_fixture_max = 3.45V
R_fixture = 10000Ohm
|   Time   V(typ)   V(min)   V(max)
0s        3.3V       3.15V      3.45V
5.76ns    3.392V     3.138V     3.575V
10.14ns   3.466V     3.238V     3.649V
16.1ns    3.5V       3.312V     3.615V
36.98ns   3.202V     3.231V     3.096V
157ns     927.4mV    1.557V     63.84mV
202.2ns   104mV      908.8mV    20.93mV
258.8ns   24.2mV     131.3mV    19.05mV
285.5ns   22.41mV    45.74mV    18.7mV
390ns     19.12mV    23.36mV    17.62mV
[Rising Waveform]
V_fixture = 3.3V
V_fixture_min = 3.15V
V_fixture_max = 3.45V
R_fixture = 10000Ohm
|   Time   V(typ)   V(min)   V(max)
0s        19.08mV    23.21mV    17.61mV
2.92ns    -40.11mV   23.21mV    -339.9mV
4.48ns    -264.3mV   18.92mV    -329.1mV
7ns       -178.8mV   -13.97mV   -63.92mV
11.26ns   376.4mV    -41.83mV   610.6mV
23.26ns   1.659V     1.15V      1.929V
33.88ns   2.282V     1.875V     2.554V
49.36ns   2.822V     2.488V     3.062V
89.26ns   3.236V     3.039V     3.41V
175.9ns   3.299V     3.148V     3.449V
[Falling Waveform]
V_fixture = 3.3V
V_fixture_min = 3.15V
V_fixture_max = 3.45V
R_fixture = 50Ohm
|   Time   V(typ)   V(min)   V(max)
0s        3.3V       3.15V      3.45V
33.58ns   3.297V     3.151V     3.4V
68.58ns   3.119V     3.108V     3.013V
139.6ns   2.577V     2.797V     2.175V
160ns     2.426V     2.701V     1.981V
184.7ns   2.25V      2.586V     1.867V
248.3ns   1.935V     2.311V     1.79V
308.2ns   1.855V     2.108V     1.768V
365.8ns   1.825V     2.014V     1.759V
800ns     1.781V     1.894V     1.747V
[Rising Waveform]
V_fixture = 3.3V
V_fixture_min = 3.15V
V_fixture_max = 3.45V
R_fixture = 50Ohm
|   Time   V(typ)   V(min)   V(max)
0s        1.78V      1.89V      1.747V
1.32ns    1.784V     1.89V      1.835V
1.96ns    1.871V     1.89V      3.096V
2.6ns     2.537V     1.89V      3.394V
3.18ns    3.025V     1.89V      3.404V
3.9ns     3.232V     1.89V      3.411V
5.64ns    3.27V      1.997V     3.425V
7.92ns    3.28V      2.82V      3.436V
10.26ns   3.288V     3.096V     3.442V
34.92ns   3.3V       3.15V      3.45V
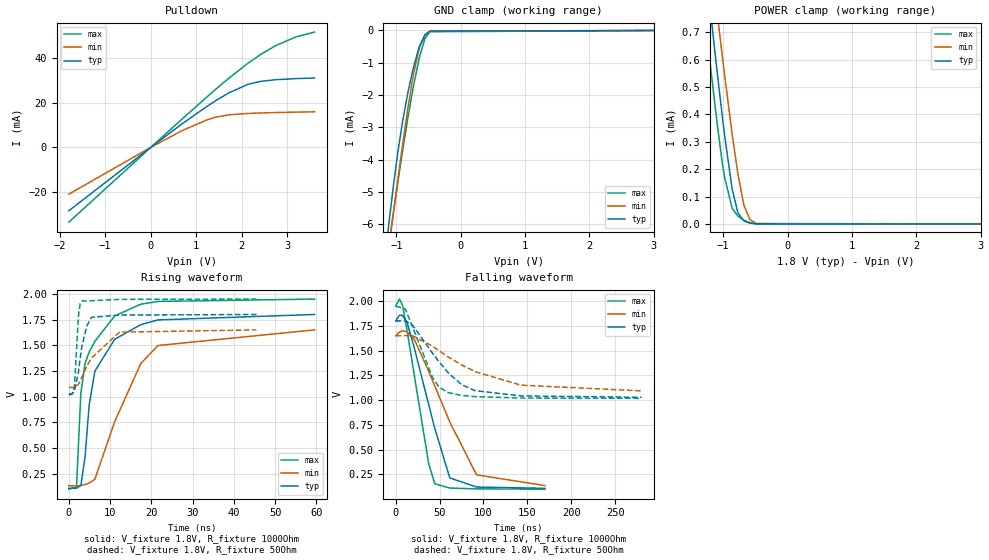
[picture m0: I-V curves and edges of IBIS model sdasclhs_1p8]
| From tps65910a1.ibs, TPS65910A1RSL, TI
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|   sdasclhs_1p8 Model
[Model]   sdasclhs_1p8
Model_type   I/O_open_drain
Polarity   Non-Inverting
Vinl = 0.54
Vinh = 1.26
Vmeas = 0.9
Vref = 1.8
Cref = 100pF
Rref = 1000
|   typ   min   max
|   (nom PVT)   (fast PVT)   (slow PVT)
C_comp   9.733e-14   7.243e-14   1.141e-13
[Model spec]
|subparameter
Vinl   0.54   0.495   0.585
Vinh   1.26   1.155   1.365
| Where nom  PVT is Nominal Process, 1.8V, 27C
|   Fast PVT is Strong Process,  1.95V, -40C
|   Slow PVT is Weak Process,   1.65V, 125C
[Voltage Range]   1.8   1.65   1.95
|Junction Temperature
[Temperature Range]   27   125   -40
[Pullup Reference]   1.8   1.65   1.95
[Pulldown Reference]   0   0   0
[Power Clamp Reference]   1.8   1.65   1.95
[GND Clamp Reference]   0   0   0
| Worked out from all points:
|   slope of the pulldown table from 0 to 0.27 V, typ, clamps not added: 64.2 ohm
|   GND clamp passes 1 mA (typ) near -0.71 V on its own axis
|   POWER clamp passes 1 mA (typ) near -1.30 V on its own axis
|   falling waveform, V_fixture 1.8V, R_fixture 1000Ohm: 20-80 % time 29.4ns typ, 43.6ns min, 20.2ns max; typ from 1.8 V to 0.109 V
|   rising waveform, V_fixture 1.8V, R_fixture 1000Ohm: 20-80 % time 4.79ns typ, 8.99ns min, 4.47ns max; typ from 0.108 V to 1.8 V
|   falling waveform, V_fixture 1.8V, R_fixture 50Ohm: 20-80 % time 42.5ns typ, 72.6ns min, 25.2ns max; typ from 1.8 V to 1.03 V
|   rising waveform, V_fixture 1.8V, R_fixture 50Ohm: 20-80 % time 1.87ns typ, 5.66ns min, 743ps max; typ from 1.03 V to 1.8 V
[Pulldown]
|   Voltage   I(typ)   I(min)   I(max)
-1.8V     -28.34mA   -20.91mA   -33.45mA
34.95mV   549uA      403uA      649.1uA
684mV     10.48mA    7.449mA    12.6mA
1.238V    18.38mA    12.33mA    22.63mA
1.447V    21.14mA    13.6mA     26.33mA
1.721V    24.43mA    14.56mA    31.03mA
2.135V    28.2mA     15.18mA    37.61mA
2.418V    29.55mA    15.41mA    41.6mA
2.749V    30.28mA    15.59mA    45.55mA
3.198V    30.77mA    15.78mA    49.48mA
3.6V      31.03mA    15.91mA    51.57mA
[GND Clamp]
|   Voltage   I(typ)   I(min)   I(max)
-1.8V     -19.24mA   -17.89mA   -19.68mA
-1.208V   -7.627mA   -8.181mA   -8.006mA
-1.112V   -5.921mA   -6.676mA   -6.595mA
-1.037V   -4.687mA   -5.527mA   -5.539mA
-968.4mV  -3.673mA   -4.501mA   -4.605mA
-901.8mV  -2.818mA   -3.535mA   -3.726mA
-820.8mV  -1.937mA   -2.426mA   -2.718mA
-735.8mV  -1.163mA   -1.391mA   -1.754mA
-643.3mV  -511.1uA   -549.4uA   -855uA
-554.3mV  -137.5uA   -140.3uA   -254.8uA
-477mV    -25.17uA   -30.69uA   -42.82uA
3.6V      0A         0A         0A
[POWER Clamp]
|   Voltage   I(typ)   I(min)   I(max)
-1.8V     2.198mA    2.387mA    1.947mA
-1.269V   932.8uA    1.137mA    723uA
-1.123V   617.8uA    832.7uA    424.9uA
-1.082V   532.4uA    749.8uA    346.2uA
-1.012V   389.7uA    609.9uA    221.5uA
-977.4mV  323.6uA    543.8uA    170.1uA
-859.5mV  126.3uA    326.8uA    56.77uA
-770.4mV  40.09uA    181.8uA    28.37uA
-676.4mV  10.97uA    67.86uA    13.4uA
-585.6mV  3.31uA     15.84uA    3.968uA
-483.3mV  385.1nA    1.578uA    290.9nA
3.6V      0A         0A         0A
[Ramp]
R_load = 1000
|   typ   min   max
dV/dt_r   1.01519/4.83044e-09   0.910473/8.94109e-09   1.11015/4.46256e-09
dV/dt_f   1.01486/2.93557e-08   0.908484/4.34787e-08   1.1101/2.01952e-08
[Falling Waveform]
V_fixture = 1.8V
V_fixture_min = 1.65V
V_fixture_max = 1.95V
R_fixture = 1000Ohm
|   Time   V(typ)   V(min)   V(max)
0s        1.8V       1.65V      1.95V
4.24ns    1.857V     1.687V     2.021V
7.8ns     1.856V     1.7V       1.96V
12.82ns   1.789V     1.691V     1.71V
20.94ns   1.536V     1.619V     1.265V
37.6ns    954.8mV    1.291V     357.2mV
44.6ns    712.4mV    1.141V     153.8mV
61.64ns   213.8mV    778.3mV    111.2mV
92.16ns   121.2mV    244.5mV    102.7mV
170ns     108.6mV    135.9mV    99.83mV
[Rising Waveform]
V_fixture = 1.8V
V_fixture_min = 1.65V
V_fixture_max = 1.95V
R_fixture = 1000Ohm
|   Time   V(typ)   V(min)   V(max)
0s        108mV      132.5mV    99.73mV
1.86ns    108.7mV    131.5mV    122.4mV
2.92ns    135.8mV    136.1mV    1.035V
3.94ns    416.2mV    144.9mV    1.324V
4.92ns    914.9mV    158.7mV    1.433V
6.32ns    1.249V     197.1mV    1.539V
11.12ns   1.559V     757.4mV    1.786V
17.44ns   1.701V     1.323V     1.9V
21.6ns    1.747V     1.498V     1.927V
59.55ns   1.8V       1.65V      1.95V
[Falling Waveform]
V_fixture = 1.8V
V_fixture_min = 1.65V
V_fixture_max = 1.95V
R_fixture = 50Ohm
|   Time   V(typ)   V(min)   V(max)
0s        1.8V       1.65V      1.95V
11.06ns   1.801V     1.652V     1.92V
19.76ns   1.751V     1.648V     1.728V
41.96ns   1.474V     1.545V     1.229V
49.54ns   1.385V     1.498V     1.129V
60.4ns    1.271V     1.433V     1.074V
75.4ns    1.154V     1.354V     1.047V
90.34ns   1.096V     1.288V     1.035V
142.6ns   1.042V     1.151V     1.021V
280ns     1.028V     1.093V     1.018V
[Rising Waveform]
V_fixture = 1.8V
V_fixture_min = 1.65V
V_fixture_max = 1.95V
R_fixture = 50Ohm
|   Time   V(typ)   V(min)   V(max)
0s        1.027V     1.09V      1.017V
800ps     1.027V     1.09V      1.024V
1.36ns    1.051V     1.09V      1.101V
2.34ns    1.239V     1.121V     1.786V
2.74ns    1.373V     1.151V     1.905V
3.2ns     1.494V     1.193V     1.933V
4.38ns    1.691V     1.3V       1.93V
5.48ns    1.773V     1.376V     1.934V
12.28ns   1.794V     1.628V     1.947V
45.48ns   1.8V       1.65V      1.95V
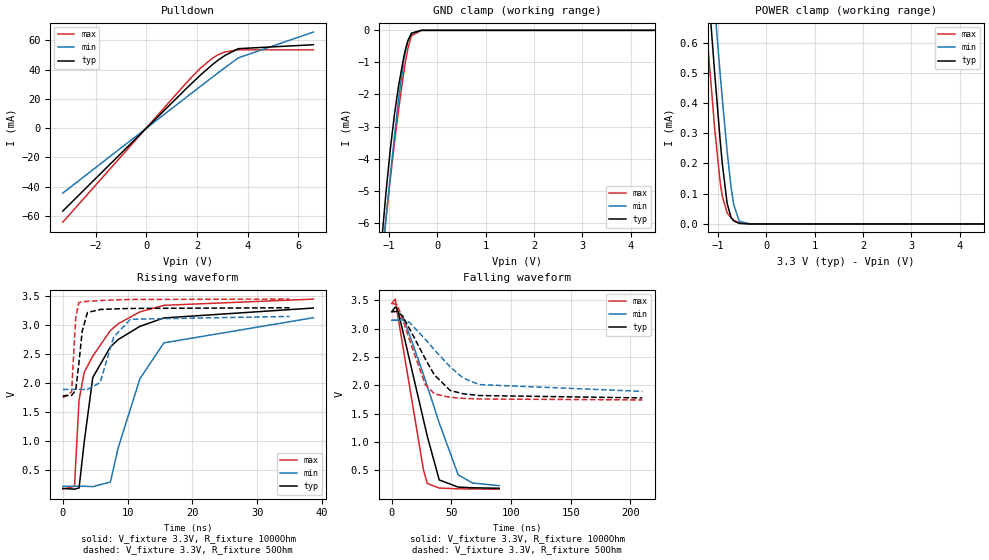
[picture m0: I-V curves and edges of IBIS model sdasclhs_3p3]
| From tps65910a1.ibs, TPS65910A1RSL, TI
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|   sdasclhs_3p3 Model
[Model]   sdasclhs_3p3
Model_type   I/O_open_drain
Polarity   Non-Inverting
Vinl = 0.99
Vinh = 2.31
Vmeas = 1.65
Vref = 3.3
Cref = 100pF
Rref = 1000
|   typ   min   max
|   (nom PVT)   (fast PVT)   (slow PVT)
C_comp   6.141e-14   5.248e-14   6.765e-14
[Model spec]
|subparameter
Vinl   0.99   0.945   1.035
Vinh   2.31   2.205   2.415
| Where nom  PVT is Nominal Process, 3.3V, 27C
|   Fast PVT is Strong Process,  3.45V, -40C
|   Slow PVT is Weak Process,   3.15V, 125C
[Voltage Range]   3.3   3.15   3.45
|Junction Temperature
[Temperature Range]   27   125   -40
[Pullup Reference]   3.3   3.15   3.45
[Pulldown Reference]   0   0   0
[Power Clamp Reference]   3.3   3.15   3.45
[GND Clamp Reference]   0   0   0
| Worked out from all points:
|   slope of the pulldown table from 0 to 0.495 V, typ, clamps not added: 58.3 ohm
|   GND clamp passes 1 mA (typ) near -0.71 V on its own axis
|   POWER clamp passes 1 mA (typ) near -1.30 V on its own axis
|   falling waveform, V_fixture 3.3V, R_fixture 1000Ohm: 20-80 % time 20.7ns typ, 27.2ns min, 15.5ns max; typ from 3.3 V to 0.186 V
|   rising waveform, V_fixture 3.3V, R_fixture 1000Ohm: 20-80 % time 4.55ns typ, 5.89ns min, 4.34ns max; typ from 0.182 V to 3.29 V
|   falling waveform, V_fixture 3.3V, R_fixture 50Ohm: 20-80 % time 23.9ns typ, 34.2ns min, 16.6ns max; typ from 3.3 V to 1.78 V
|   rising waveform, V_fixture 3.3V, R_fixture 50Ohm: 20-80 % time 859ps typ, 2.21ns min, 459ps max; typ from 1.78 V to 3.3 V
[Pulldown]
|   Voltage   I(typ)   I(min)   I(max)
-3.3V     -56.75mA   -44.46mA   -64.36mA
1.645V    28.15mA    21.96mA    32.17mA
2.158V    36.57mA    28.78mA    41.32mA
2.637V    43.76mA    35.14mA    48.1mA
2.833V    46.39mA    37.72mA    50.11mA
3.114V    49.74mA    41.39mA    52.13mA
3.635V    54.33mA    48.04mA    53.51mA
6.6V      57.01mA    65.66mA    53.51mA
[GND Clamp]
|   Voltage   I(typ)   I(min)   I(max)
-3.3V     -48.39mA   -44.92mA   -50.25mA
-1.164V   -6.846mA   -7.5mA     -7.361mA
-1.063V   -5.1mA     -5.92mA    -5.899mA
-971.2mV  -3.713mA   -4.544mA   -4.643mA
-884.4mV  -2.615mA   -3.29mA    -3.503mA
-802.1mV  -1.754mA   -2.183mA   -2.497mA
-691.8mV  -824.8uA   -943.6uA   -1.301mA
-656.7mV  -590.7uA   -646.3uA   -971.5uA
-605.6mV  -317.6uA   -327uA     -558.5uA
-533.1mV  -90.79uA   -94.86uA   -168.5uA
-330mV    -364nA     -1.09uA    -250.7nA
6.6V      0A         0A         0A
[POWER Clamp]
|   Voltage   I(typ)   I(min)   I(max)
-3.3V     6.427mA    5.735mA    6.456mA
-1.353V   1.121mA    1.32mA     903.5uA
-1.196V   772.1uA    982uA      570uA
-1.064V   495.7uA    714.1uA    313.1uA
-950.4mV  273.4uA    492.5uA    135.5uA
-907.5mV  198.7uA    412.7uA    91.66uA
-808.5mV  68.66uA    240.8uA    36.76uA
-726.3mV  20.89uA    121.5uA    20.71uA
-671.1mV  10.3uA     63.31uA    12.71uA
-556.4mV  1.987uA    8.722uA    2.191uA
-330mV    0A         27.99nA    0A
6.6V      0A         0A         0A
[Ramp]
R_load = 1000
|   typ   min   max
dV/dt_r   1.87103/4.57794e-09   1.75909/5.98479e-09   1.9689/4.33135e-09
dV/dt_f   1.86867/2.06842e-08   1.75072/2.72391e-08   1.9681/1.55086e-08
[Falling Waveform]
V_fixture = 3.3V
V_fixture_min = 3.15V
V_fixture_max = 3.45V
R_fixture = 1000Ohm
|   Time   V(typ)   V(min)   V(max)
0s        3.3V       3.15V      3.45V
2.968ns   3.382V     3.15V      3.524V
4.768ns   3.348V     3.15V      3.265V
9.484ns   2.941V     3.217V     2.672V
26.73ns   1.381V     2.184V     496.8mV
29.76ns   1.106V     1.987V     270.8mV
39.81ns   332mV      1.337V     189.3mV
55.68ns   206.2mV    422.8mV    175.9mV
67.58ns   194.5mV    279mV      172.9mV
90ns      185.5mV    232.1mV    169.8mV
[Rising Waveform]
V_fixture = 3.3V
V_fixture_min = 3.15V
V_fixture_max = 3.45V
R_fixture = 1000Ohm
|   Time   V(typ)   V(min)   V(max)
0s        181.5mV    218.1mV    168.4mV
1.804ns   168.6mV    218.1mV    217.4mV
2.51ns    189.2mV    218.1mV    1.706V
3.306ns   984.8mV    218.1mV    2.188V
4.626ns   2.096V     212.4mV    2.465V
7.338ns   2.623V     290.7mV    2.906V
8.554ns   2.752V     884.6mV    3.024V
11.9ns    2.979V     2.075V     3.229V
15.6ns    3.124V     2.694V     3.342V
38.66ns   3.295V     3.128V     3.449V
[Falling Waveform]
V_fixture = 3.3V
V_fixture_min = 3.15V
V_fixture_max = 3.45V
R_fixture = 50Ohm
|   Time   V(typ)   V(min)   V(max)
0s        3.3V       3.15V      3.45V
4.476ns   3.305V     3.15V      3.425V
8.816ns   3.23V      3.155V     3.191V
14.83ns   3.004V     3.113V     2.805V
28.15ns   2.467V     2.814V     2.013V
35.73ns   2.186V     2.629V     1.852V
48.97ns   1.911V     2.328V     1.79V
59.87ns   1.853V     2.13V      1.772V
73.31ns   1.822V     2.015V     1.761V
210ns     1.78V      1.895V     1.744V
[Rising Waveform]
V_fixture = 3.3V
V_fixture_min = 3.15V
V_fixture_max = 3.45V
R_fixture = 50Ohm
|   Time   V(typ)   V(min)   V(max)
0s        1.78V      1.89V      1.747V
1.352ns   1.786V     1.89V      1.846V
1.994ns   1.876V     1.89V      3.126V
2.464ns   2.324V     1.89V      3.387V
2.988ns   2.892V     1.89V      3.401V
3.8ns     3.218V     1.89V      3.41V
5.758ns   3.27V      2.007V     3.425V
7.83ns    3.28V      2.789V     3.435V
10.43ns   3.288V     3.102V     3.443V
35ns      3.3V       3.15V      3.45V
